VERSION 5.7 ;
  NOWIREEXTENSIONATPIN ON ;
  DIVIDERCHAR "/" ;
  BUSBITCHARS "[]" ;
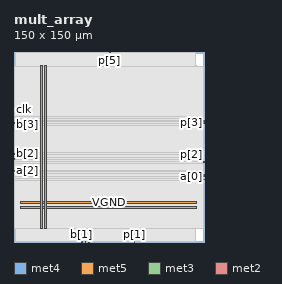
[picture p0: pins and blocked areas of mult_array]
MACRO mult_array
  CLASS BLOCK ;
  FOREIGN mult_array ;
  ORIGIN 0.000 0.000 ;
  SIZE 150.000 BY 150.000 ;
  PIN VGND
    DIRECTION INOUT ;
    USE GROUND ;
    PORT
      LAYER met4 ;
        RECT 24.340 10.640 25.940 138.960 ;
    END
    PORT
      LAYER met5 ;
        RECT 5.520 30.030 144.440 31.630 ;
    END
  END VGND
  PIN VPWR
    DIRECTION INOUT ;
    USE POWER ;
    PORT
      LAYER met4 ;
        RECT 21.040 10.640 22.640 138.960 ;
    END
    PORT
      LAYER met5 ;
        RECT 5.520 26.730 144.440 28.330 ;
    END
  END VPWR
  PIN a[0]
    DIRECTION INPUT ;
    USE SIGNAL ;
    ANTENNAGATEAREA 0.159000 ;
    PORT
      LAYER met3 ;
        RECT 149.400 51.720 150.000 52.320 ;
    END
  END a[0]
  PIN a[1]
    DIRECTION INPUT ;
    USE SIGNAL ;
    ANTENNAGATEAREA 0.159000 ;
    PORT
      LAYER met2 ;
        RECT 58.970 0.000 59.250 0.280 ;
    END
  END a[1]
  PIN a[2]
    DIRECTION INPUT ;
    USE SIGNAL ;
    ANTENNAGATEAREA 0.159000 ;
    PORT
      LAYER met3 ;
        RECT 0.000 55.800 0.600 56.400 ;
    END
  END a[2]
  PIN a[3]
    DIRECTION INPUT ;
    USE SIGNAL ;
    ANTENNAGATEAREA 0.159000 ;
    PORT
      LAYER met3 ;
        RECT 0.000 65.320 0.600 65.920 ;
    END
  END a[3]
  PIN b[0]
    DIRECTION INPUT ;
    USE SIGNAL ;
    ANTENNAGATEAREA 0.159000 ;
    PORT
      LAYER met2 ;
        RECT 56.210 0.000 56.490 0.280 ;
    END
  END b[0]
  PIN b[1]
    DIRECTION INPUT ;
    USE SIGNAL ;
    ANTENNAGATEAREA 0.159000 ;
    PORT
      LAYER met2 ;
        RECT 53.450 0.000 53.730 0.280 ;
    END
  END b[1]
  PIN b[2]
    DIRECTION INPUT ;
    USE SIGNAL ;
    ANTENNAGATEAREA 0.159000 ;
    PORT
      LAYER met3 ;
        RECT 0.000 69.400 0.600 70.000 ;
    END
  END b[2]
  PIN b[3]
    DIRECTION INPUT ;
    USE SIGNAL ;
    ANTENNAGATEAREA 0.159000 ;
    PORT
      LAYER met3 ;
        RECT 0.000 92.520 0.600 93.120 ;
    END
  END b[3]
  PIN clk
    DIRECTION INPUT ;
    USE SIGNAL ;
    ANTENNAGATEAREA 0.852000 ;
    PORT
      LAYER met3 ;
        RECT 0.000 97.960 0.600 98.560 ;
    END
  END clk
  PIN p[0]
    DIRECTION OUTPUT ;
    USE SIGNAL ;
    ANTENNADIFFAREA 0.445500 ;
    PORT
      LAYER met3 ;
        RECT 149.400 53.080 150.000 53.680 ;
    END
  END p[0]
  PIN p[1]
    DIRECTION OUTPUT ;
    USE SIGNAL ;
    ANTENNADIFFAREA 0.445500 ;
    PORT
      LAYER met2 ;
        RECT 94.850 0.000 95.130 0.280 ;
    END
  END p[1]
  PIN p[2]
    DIRECTION OUTPUT ;
    USE SIGNAL ;
    ANTENNADIFFAREA 0.445500 ;
    PORT
      LAYER met3 ;
        RECT 149.400 62.600 150.000 63.200 ;
    END
  END p[2]
  PIN p[3]
    DIRECTION OUTPUT ;
    USE SIGNAL ;
    ANTENNADIFFAREA 0.445500 ;
    PORT
      LAYER met3 ;
        RECT 149.400 93.880 150.000 94.480 ;
    END
  END p[3]
  PIN p[4]
    DIRECTION OUTPUT ;
    USE SIGNAL ;
    ANTENNADIFFAREA 0.445500 ;
    PORT
      LAYER met3 ;
        RECT 149.400 95.240 150.000 95.840 ;
    END
  END p[4]
  PIN p[5]
    DIRECTION OUTPUT ;
    USE SIGNAL ;
    ANTENNADIFFAREA 0.445500 ;
    PORT
      LAYER met2 ;
        RECT 75.530 149.720 75.810 150.000 ;
    END
  END p[5]
  PIN p[6]
    DIRECTION OUTPUT ;
    USE SIGNAL ;
    ANTENNADIFFAREA 0.445500 ;
    PORT
      LAYER met3 ;
        RECT 0.000 93.880 0.600 94.480 ;
    END
  END p[6]
  PIN p[7]
    DIRECTION OUTPUT ;
    USE SIGNAL ;
    ANTENNADIFFAREA 0.445500 ;
    PORT
      LAYER met2 ;
        RECT 56.210 149.720 56.490 150.000 ;
    END
  END p[7]
  PIN rst_n
    DIRECTION INPUT ;
    USE SIGNAL ;
    ANTENNAGATEAREA 0.159000 ;
    PORT
      LAYER met3 ;
        RECT 149.400 49.000 150.000 49.600 ;
    END
  END rst_n
  OBS
      LAYER nwell ;
        RECT 5.330 10.795 144.630 138.910 ;
      LAYER li1 ;
        RECT 5.520 10.795 144.440 138.805 ;
      LAYER met1 ;
        RECT 1.450 10.640 144.440 138.960 ;
      LAYER met2 ;
        RECT 1.470 149.440 55.930 149.720 ;
        RECT 56.770 149.440 75.250 149.720 ;
        RECT 76.090 149.440 142.970 149.720 ;
        RECT 1.470 0.560 142.970 149.440 ;
        RECT 1.470 0.280 53.170 0.560 ;
        RECT 54.010 0.280 55.930 0.560 ;
        RECT 56.770 0.280 58.690 0.560 ;
        RECT 59.530 0.280 94.570 0.560 ;
        RECT 95.410 0.280 142.970 0.560 ;
      LAYER met3 ;
        RECT 0.600 98.960 149.400 138.885 ;
        RECT 1.000 97.560 149.400 98.960 ;
        RECT 0.600 96.240 149.400 97.560 ;
        RECT 0.600 94.880 149.000 96.240 ;
        RECT 1.000 93.480 149.000 94.880 ;
        RECT 1.000 92.120 149.400 93.480 ;
        RECT 0.600 70.400 149.400 92.120 ;
        RECT 1.000 69.000 149.400 70.400 ;
        RECT 0.600 66.320 149.400 69.000 ;
        RECT 1.000 64.920 149.400 66.320 ;
        RECT 0.600 63.600 149.400 64.920 ;
        RECT 0.600 62.200 149.000 63.600 ;
        RECT 0.600 56.800 149.400 62.200 ;
        RECT 1.000 55.400 149.400 56.800 ;
        RECT 0.600 54.080 149.400 55.400 ;
        RECT 0.600 51.320 149.000 54.080 ;
        RECT 0.600 50.000 149.400 51.320 ;
        RECT 0.600 48.600 149.000 50.000 ;
        RECT 0.600 10.715 149.400 48.600 ;
  END
END mult_array
END LIBRARY

